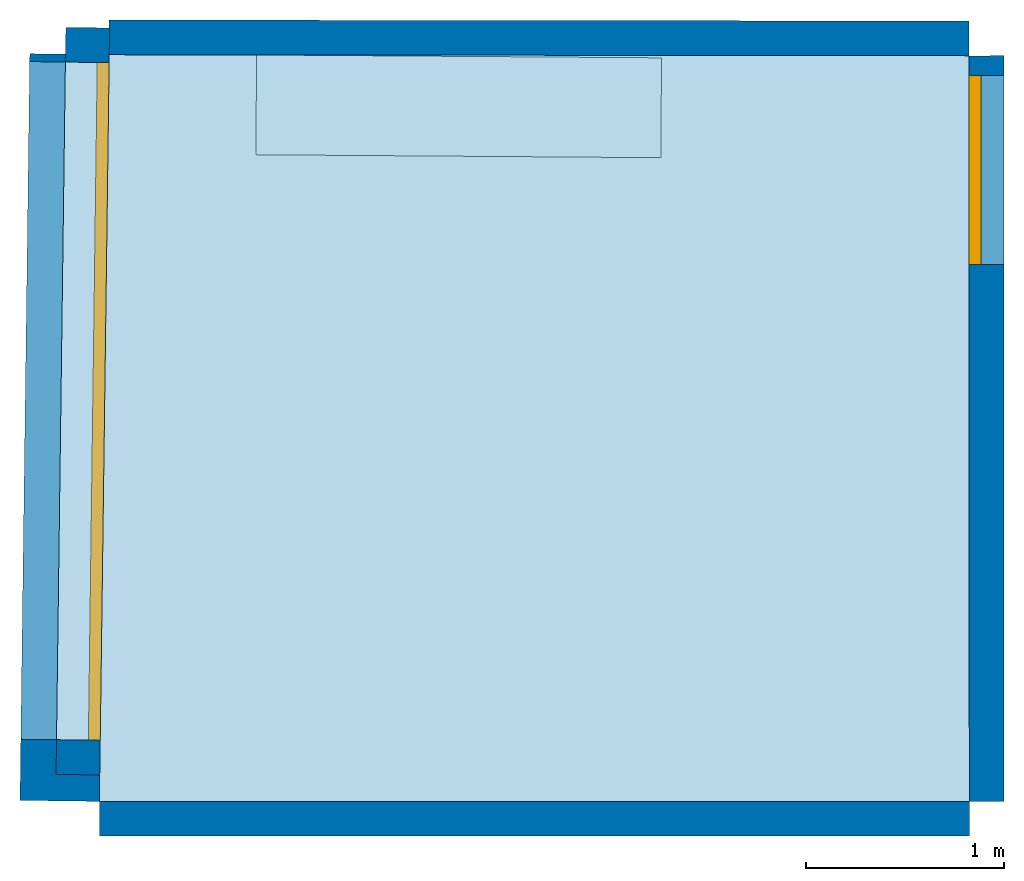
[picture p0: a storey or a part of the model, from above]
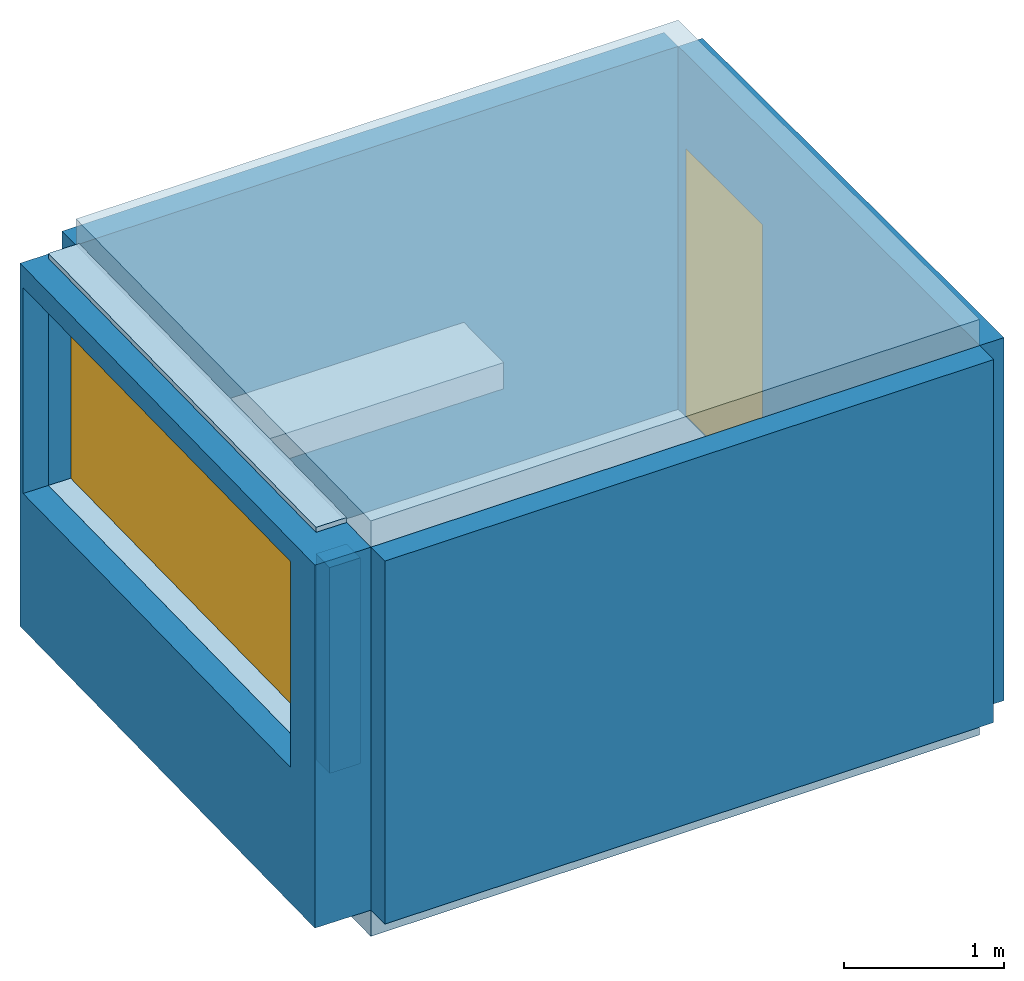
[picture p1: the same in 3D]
Properties of the parts of a building model (IFC2X3)

# File
Description: ViewDefinition[CoordinationView_V2.0]
File name: C:\Users\g.coskunoglu\Desktop\Büroraum.ifc
Time: 2023-01-02T11:21:28
Written by: IFC 2x3 writer version 1.1
Made in: IFCExportDemo.exe

# IfcBuildingStorey, 600 EG
In: Gebäude
Elevation: 0 m

# IfcDoor, Door
In: 600 EG
OverallHeight: 2.03233 m; OverallWidth: 0.950595 m

# IfcSlab (5)
In: 600 EG
PredefinedType: FLOOR
Name
2 x Ground
3 x Ceiling

# IfcWindow, Window
In: 600 EG
OverallHeight: 1.56685 m; OverallWidth: 3.41457 m
